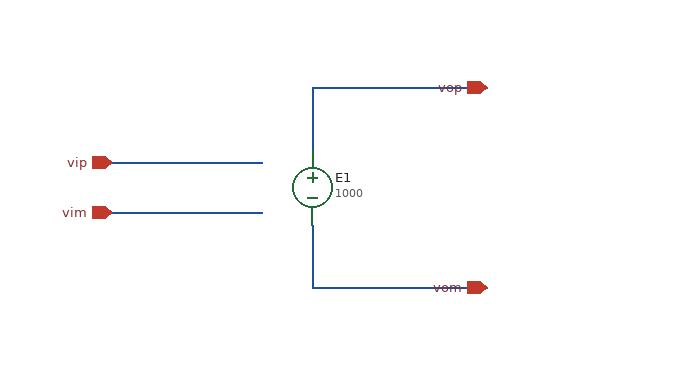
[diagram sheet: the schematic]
v {xschem version=3.4.8RC file_version=1.2}
G {}
K {}
V {}
S {}
E {}
N -160 -80 -40 -80 {lab=vip}
N -160 -40 -40 -40 {lab=vim}
N -0 -140 -0 -90 {lab=vop}
N -0 -140 140 -140 {lab=vop}
N 0 -30 0 20 {lab=vom}
N 0 20 140 20 {lab=vom}
C {vcvs.sym} 0 -60 0 0 {name=E1 value=1000}
C {iopin.sym} -160 -80 2 0 {name=p2 lab=vip}
C {iopin.sym} -160 -40 2 0 {name=p3 lab=vim}
C {iopin.sym} 140 -140 0 0 {name=p4 lab=vop}
C {iopin.sym} 140 20 0 0 {name=p1 lab=vom}
